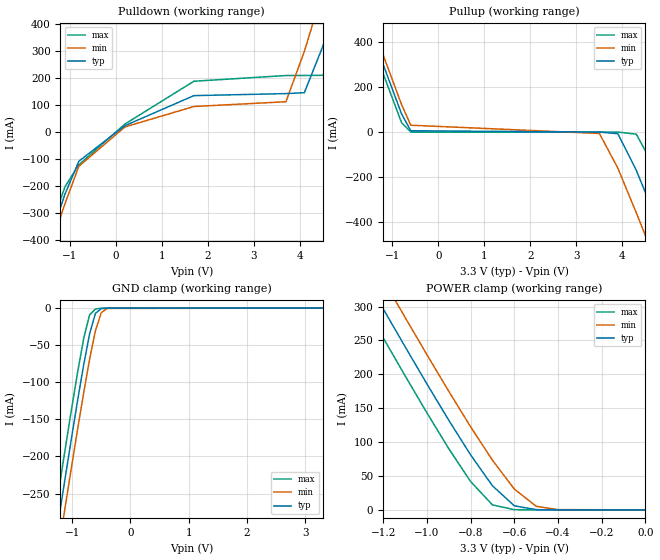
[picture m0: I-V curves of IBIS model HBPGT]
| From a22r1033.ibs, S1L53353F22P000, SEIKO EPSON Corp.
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[Model]   HBPGT
Model_type   I/O
Polarity   Non-Inverting
Vinh=2.0V
Vinl=0.8V
|   typ   min   max
C_comp   5.0pF   4.0pF   6.0pF
|   typ   min   max
[Voltage range]   3.3   3.0   3.6
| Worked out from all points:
|   slope of the pulldown table from 0 to 0.495 V, typ, clamps not added: 8.88 ohm
|   GND clamp passes 1 mA (typ) near -0.51 V on its own axis
|   POWER clamp passes 1 mA (typ) near -0.51 V on its own axis
[Pulldown]
|   Voltage   I(typ)   I(min)   I(max)
-3.3V     -1.365A    -1.401A    -1.33A
-1.7V     -529.5mA   -566.9mA   -493.2mA
-1.1V     -229.2mA   -264.4mA   -201.9mA
-800mV    -107.9mA   -126.6mA   -121mA
200mV     23.74mA    19.01mA    29.63mA
1.7V      135.1mA    94.74mA    188.4mA
3.7V      142.6mA    112.5mA    209.5mA
4.1V      146mA      298.6mA    209.8mA
4.5V      316.8mA    521mA      210.2mA
4.9V      540.2mA    749.4mA    339.3mA
5.3V      769.7mA    980.3mA    562.8mA
6.6V      1.527A     1.738A     1.318A
[Pullup]
|   Voltage   I(typ)   I(min)   I(max)
-3.3V     1.514A     1.553A     1.476A
-1.6V     524.3mA    566.8mA    482.3mA
-1.5V     467mA      509.6mA    424.7mA
-800mV    81.11mA    122.6mA    41.82mA
-600mV    5.969mA    30.7mA     281.7uA
3.5V      -273.4nA   -6.157mA   -6.736nA
3.9V      -7.117mA   -160.6mA   -899.7nA
4.3V      -170mA     -359.4mA   -9.189mA
4.5V      -269.6mA   -461.5mA   -84mA
4.9V      -474.2mA   -667.8mA   -281.6mA
5.3V      -681.8mA   -875.9mA   -487.9mA
6.6V      -1.364A    -1.557A    -1.17A
[GND_clamp]
|   Voltage   I(typ)   I(min)   I(max)
-3.3V     -1.364A    -1.4A      -1.329A
-1.3V     -320.3mA   -359.4mA   -281.6mA
-1.2V     -269.6mA   -308.9mA   -230.8mA
-1.1V     -219.5mA   -258.7mA   -180.6mA
-1V       -170.1mA   -209.2mA   -131.4mA
-900mV    -121.9mA   -160.6mA   -84mA
-800mV    -75.86mA   -113.5mA   -40.55mA
-700mV    -34.75mA   -69.08mA   -9.194mA
-600mV    -7.118mA   -30.46mA   -1.232mA
-500mV    -657.9uA   -6.157mA   -258.3uA
-400mV    -61.96uA   -470.6uA   -20.17uA
3.3V      8.542nA    15.7uA     7.344nA
[POWER_clamp]
|   Voltage   I(typ)   I(min)   I(max)
-3.3V     1.514A     1.553A     1.476A
-1.3V     353.1mA    396.1mA    310.4mA
-1.2V     296.7mA    339.9mA    253.9mA
-1.1V     240.9mA    284.1mA    198mA
-1V       185.9mA    229mA      143.2mA
-900mV    132.3mA    175mA      90.33mA
-800mV    81.11mA    122.6mA    41.82mA
-700mV    35.52mA    73.27mA    7.314mA
-600mV    5.969mA    30.7mA     281.7uA
-500mV    284.1uA    5.285mA    30.01uA
-400mV    15.7uA     326.5uA    2.386uA
0V        8.542nA    18.22nA    8.664nA
[Ramp]
|   V_typ   V_min   V_max
dV/dt_r   1.98/0.68n   1.80/0.94n   2.16/0.45n
dV/dt_f   1.98/0.35n   1.80/0.52n   2.16/0.26n
R_load = 5000
